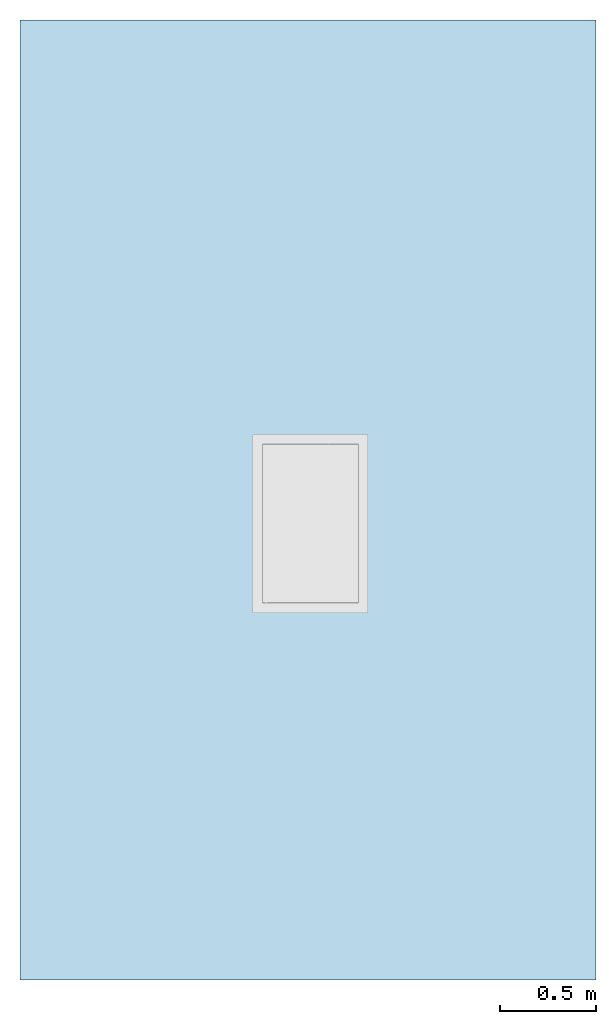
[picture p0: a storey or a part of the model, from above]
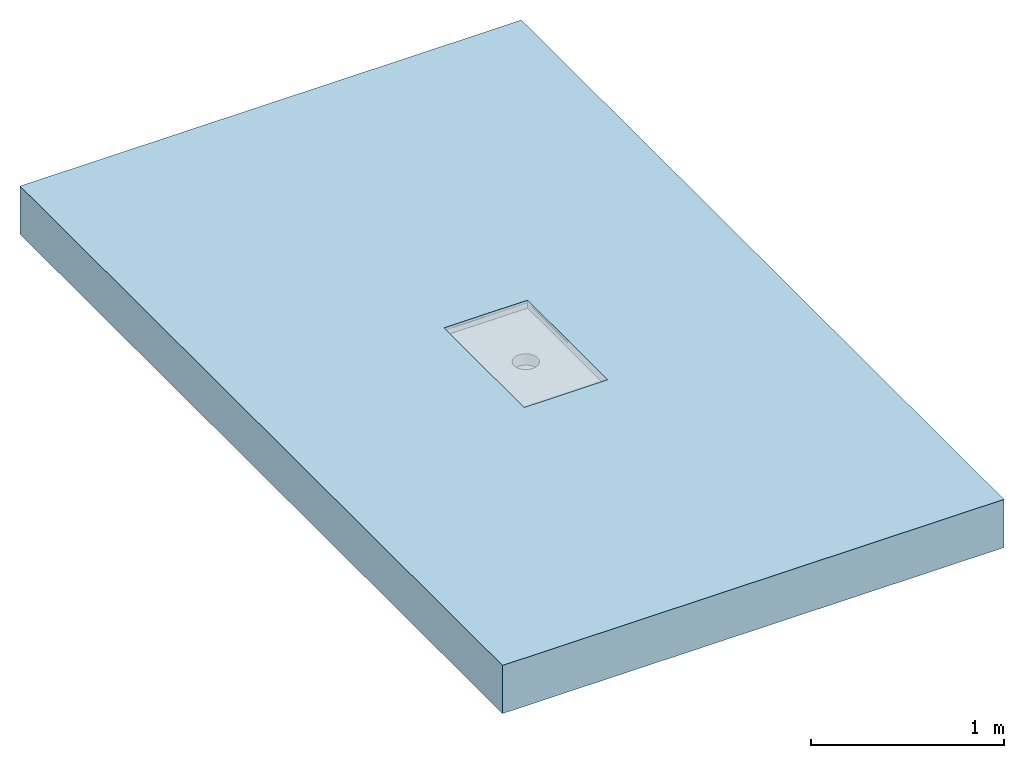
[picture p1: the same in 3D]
Properties of the parts of a building model (IFC2X3)

# File
Description: ViewDefinition [CoordinationView]
File name: Project Number
Time: 2016-11-22T09:59:32
Written by: The EXPRESS Data Manager Version 5.01.0100.02.64mod : 6 Jun 2012
Made in: 20130308_1515(x64) - Exporter 2014.0.2013.0308 - Default UI
Comment: STEP Physical File produced by: The EXPRESS Data Manager Version 5.01.0100.02.64mod : 6 Jun 2012 * Module: EDMstepFileFactory/EDMstandAlone * Creation date: Tue Nov 22 09:59:32 2016 * Host: IN-BLR-PC-0012 * Database: C:\Users\pakumar\AppData\Local\Temp\{BC879651-D9CA-477F-9550-3CB7831999B2}\ifc * Database version: 5507 * Database creation date: Tue Nov 22 09:59:31 2016 * Schema: IFC2X3 * Model: DataRepository.ifc * Model creation date: Tue Nov 22 09:59:31 2016 * Header model: DataRepository.ifc_HeaderModel * Header model creation date: Tue Nov 22 09:59:31 2016 * EDMuser: sdai-user * EDMgroup: sdai-group * License ID and type: 5605 : Permanent license. Expiry date: * EDMstepFileFactory options: 020000

# IfcProject, Project Number
LongName: Project Name; Phase: Project Status

# IfcSite, Default
RefLatitude: 42, 21, 30, 344238; RefLongitude: -71, -3, -35, -194702; RefElevation: 0 mm

# IfcBuilding
Pset_BuildingCommon - NumberOfStoreys: 1
Other - Project Issue Date: Issue Date; Project Number: Project Number; Project Status: Project Status; Client Name: Owner; Project Name: Project Name; Project Address: Enter address here

# IfcBuildingStorey, Level 1
LongName: Level 1; Elevation: 0 mm
Constraints - Elevation Base: Project Base Point; Elevation: 0 mm
Graphics - Line Weight: 1; Symbol at End 2 Default: yes; Symbol at End 1 Default: no; Color: 0; Line Pattern: Grid Line 1/2"; Symbol: Level Head - Circle: Level Head - Circle
Identity Data - Building Story: yes; Name: Level 1; Structural: no
Dimensions - Computation Height: 0 mm

# IfcFlowTerminal: 416751 - Hygienic Extended Channel - with Gully 157 - 800mm LG - 500mm Wide, ACO Tray Channel - Hygienic - Extended - 500mm Wide:416751 - Hygienic Extended Channel - with Gully 157 - 800mm LG - 500mm Wide:433353
In: Level 1
Material: Stainless Steel AISI 304, Stainless Steel AISI 304 - Grating
Construction - Detail - Outlet 200: no; Detail - Outlet 142mm: yes; Grating: yes; 416828 - 468 x 499mm - Ladder Grating - R50 - Stainless Steel 1.4301: no; 416892 - 468 x 499mm - Mesh Grating - L15 - Stainless Steel 1.4301: no; 416832 - 468 x 499mm - Ladder Grating - M125 - Stainless Steel 1.4301: no; 416872 - 468 x 499mm - Mesh Grating - L15 - Stainless Steel 1.4301: yes; 416830 - 468 x 398mm - Ladder Grating - R50 - Stainless Steel 1.4301: no; 416834 - 468 x 398mm - Ladder Grating - M125 - Stainless Steel 1.4301: no; 416874 - 468 x 398mm - Mesh Grating - L15 - Stainless Steel 1.4301: no; 416894 - 468 x 398mm - Mesh Grating - L15 - Stainless Steel 1.4301: no
Identity Data - Mark: 28; Watermarked With: BIM Manager Premium Suite.; Telephone: +44 (0)1462 816666; Watermarked By: www.acobd.com; Website: www.acobd.com; Fax: +44 (0)1462 851490; E-mail Technical: abdtechnical@aco.co.uk; Cost: 0; Watermark1: This file is the property of ACO Technologies PLC.; Manufacturer: ACO Building Drainage; E-mail Sales: abdcommercial@aco.co.uk; Watermark2: This file is water marked and users are prohibited to reproduce, adapt, distribute this information.; Address: ACO Business Centre, Caxton Road, Bedford, MK41 0LF
Mechanical - System Classification: Sanitary
Constraints - Level: Level: Level 1
Phasing - Phase Created: New Construction
Pset_ManufacturerTypeInformation - Manufacturer: ACO Building Drainage
General - Product Description: ACO Hygiene First Extended Kitchen Tray Channel 500 x 830 / 142 Dia Outlet & Foul Air Trap; Channel Material: Stainless steel 1.4301 (EN 10088); Foul air trap Recycled material content: 0%; Weight (Kg): 9.8; Product Code: 416751; Product Range: ACO Hygiene First; Foul air trap seal Colour: Black; Load Class: A15 - C250 (EN 1253); Maintenance guidelines: http://issuu.com/acobuildingdrainage/docs/aco_hygiene_first_catalogue/17?e=0; Channel Recycled material content: 20 - 30 %; Channel Colour: passivated stainless steel surface ( matt grey); Product Standard: EN 1253 / EN 1672 / EN ISO 14159; Channel Dimension: 500 x 830; Foul air trap seal Material: NBR; Price: POA - contact ACO; Channel Recyclable: Fully recyclable; Foul air trap Recyclable: Fully recyclable; Installation guidelines: http://issuu.com/acobuildingdrainage/docs/aco_hygiene_first_catalogue/17?e=0; Product Type: Extended Kitchen Tray Channel; Outlet Diameter (mm): 142
Dimensions - Depth: 29 mm; Length Channel: -770 mm; Number of gratings: 2; Invert Depth: 50 mm; Grating Length: 499 mm; Grating Height: 21 mm; Outside Outlet Rad: 71 mm; Endplate Position: 800 mm; Grating Void Cut Length: 500 mm; Outlet: 142 mm; Inside Outlet Rad: 66 mm; End Plate: 800 mm; End Connection Plate Start: -770 mm; End Connection Plate End: -800 mm; Floor Cut Void Height: 62.8 mm; x: -815 mm; Spigot Distance: 400 mm
Model Properties - Grating Product Code 416892: N/A; Grating Product Code 416828: N/A; Grating Product Code 416832: N/A; Grating Product Code 416894: Load Class L 15 (EN 1253) - Mesh Grate - Stainless steel 1.4301 (EN 10088) - 468 x 398 - 5.2kg; Grating Product Code 416834: Load Class M 125 (EN 1253) - Ladder Grate - Stainless steel 1.4301 (EN 10088) - 468 x 398 - 12.5kg; Grating Product Code 416872: N/A; Grating Product Code 416874: Load Class L 15 (EN 1253) - Mesh Grate - Stainless steel 1.4301 (EN 10088) - 468 x 398 - 5kg; Grating Product Code 416830: Load Class R 50 (EN 1253) - Ladder Grate - Stainless steel 1.4301 (EN 10088) - 468 x 398 - 12.5kg
Other - Number mesh: 17; Invert Depth Detail: 51.5 mm; Hygienic Standard Channel - 800mm LG - 500mm Wide: yes; Hygienic Standard Channel - 1000mm LG - 500mm Wide: no; Spigot Outlets Channels: yes; Flow: 0.0988811 m3/s; Hygienic Standard Channel - 500mm LG - 500mm Wide: no

# IfcOpeningElement: Recess
In: Level 1
Constraints - Height Offset From Level: 0 mm; Level: Level: Level 1; Room Bounding: yes; Related to Mass: no
Dimensions - Volume: 160.679 ft3; Thickness: 304.8 mm; Area: 161.459 ft2; Perimeter: 16000 mm
Phasing - Phase Created: New Construction
Structural - Enable Analytical Model: no; Structural: no
Construction - Function: Interior; Default Thickness: 304.8 mm
Identity Data - Assembly Code: B1010; Assembly Description: Floor Construction
Graphics - Coarse Scale Fill Color: 0
Analytical Properties - Absorptance: 0.7; Roughness: 3

# IfcSlab: Floor:Generic - 12", Floor:Generic - 12":184145
In: Level 1
PredefinedType: FLOOR; Material: Default Floor 304.8 mm
Constraints - Height Offset From Level: 0 mm; Level: Level: Level 1; Room Bounding: yes; Related to Mass: no
Dimensions - Volume: 160.679 ft3; Thickness: 304.8 mm; Area: 161.459 ft2; Perimeter: 16000 mm
Phasing - Phase Created: New Construction
Structural - Enable Analytical Model: no; Structural: no
Pset_SlabCommon - Reference: Generic - 12"; IsExternal: no; LoadBearing: yes
Construction - Function: Interior; Default Thickness: 304.8 mm
Identity Data - Assembly Code: B1010; Assembly Description: Floor Construction
Graphics - Coarse Scale Fill Color: 0
Analytical Properties - Absorptance: 0.7; Roughness: 3
